One B-rep face of a CAD part: STEP entity #54834.
In plain terms, the planar face has unit normal (0, 0, 1).
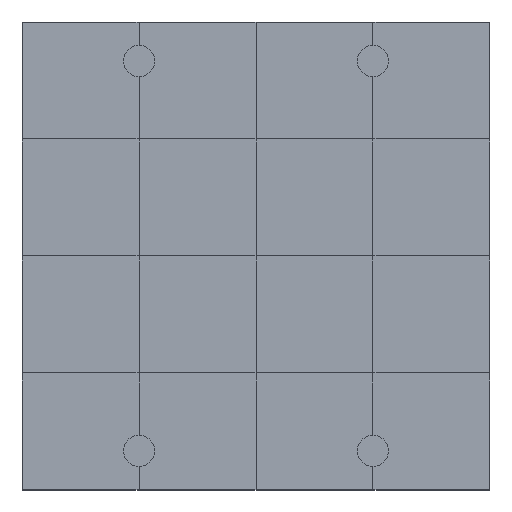
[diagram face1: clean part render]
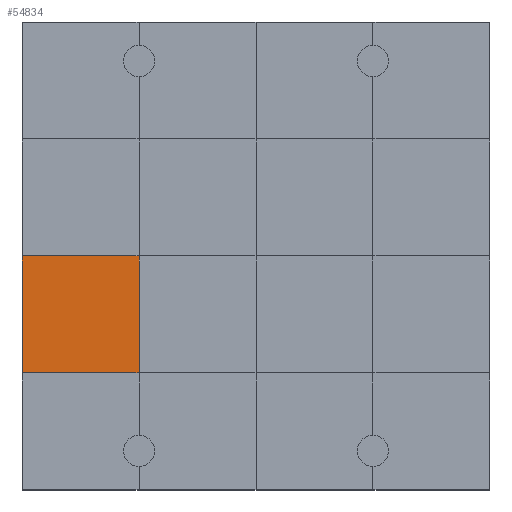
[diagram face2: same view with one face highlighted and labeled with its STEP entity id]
Its self-contained STEP definition (entity closure, numbers rounded to 3 decimals):
#54384 = VERTEX_POINT('',#54385);
#54385 = CARTESIAN_POINT('',(0.,3.,1.2));
#54399 = PLANE('',#54400);
#54400 = AXIS2_PLACEMENT_3D('',#54401,#54402,#54403);
#54401 = CARTESIAN_POINT('',(0.,3.,0.));
#54402 = DIRECTION('',(1.,0.,-0.));
#54403 = DIRECTION('',(0.,0.,1.));
#54425 = PLANE('',#54426);
#54426 = AXIS2_PLACEMENT_3D('',#54427,#54428,#54429);
#54427 = CARTESIAN_POINT('',(0.,0.,1.2));
#54428 = DIRECTION('',(0.,0.,1.));
#54429 = DIRECTION('',(1.,0.,-0.));
#54576 = VERTEX_POINT('',#54577);
#54577 = CARTESIAN_POINT('',(3.,3.,1.2));
#54598 = EDGE_CURVE('',#54384,#54576,#54599,.T.);
#54599 = SURFACE_CURVE('',#54600,(#54604,#54611),.PCURVE_S1.);
#54600 = LINE('',#54601,#54602);
#54601 = CARTESIAN_POINT('',(0.,3.,1.2));
#54602 = VECTOR('',#54603,1.);
#54603 = DIRECTION('',(1.,0.,-0.));
#54604 = PCURVE('',#54425,#54605);
#54605 = DEFINITIONAL_REPRESENTATION('',(#54606),#54610);
#54606 = LINE('',#54607,#54608);
#54607 = CARTESIAN_POINT('',(0.,3.));
#54608 = VECTOR('',#54609,1.);
#54609 = DIRECTION('',(1.,0.));
#54610 = ( GEOMETRIC_REPRESENTATION_CONTEXT(2) 
PARAMETRIC_REPRESENTATION_CONTEXT() REPRESENTATION_CONTEXT('2D SPACE',''
  ) );
#54611 = PCURVE('',#54612,#54617);
#54612 = PLANE('',#54613);
#54613 = AXIS2_PLACEMENT_3D('',#54614,#54615,#54616);
#54614 = CARTESIAN_POINT('',(0.,3.,1.2));
#54615 = DIRECTION('',(0.,0.,1.));
#54616 = DIRECTION('',(1.,0.,-0.));
#54617 = DEFINITIONAL_REPRESENTATION('',(#54618),#54622);
#54618 = LINE('',#54619,#54620);
#54619 = CARTESIAN_POINT('',(0.,0.));
#54620 = VECTOR('',#54621,1.);
#54621 = DIRECTION('',(1.,0.));
#54622 = ( GEOMETRIC_REPRESENTATION_CONTEXT(2) 
PARAMETRIC_REPRESENTATION_CONTEXT() REPRESENTATION_CONTEXT('2D SPACE',''
  ) );
#54657 = VERTEX_POINT('',#54658);
#54658 = CARTESIAN_POINT('',(0.,6.,1.2));
#54684 = EDGE_CURVE('',#54384,#54657,#54685,.T.);
#54685 = SURFACE_CURVE('',#54686,(#54690,#54697),.PCURVE_S1.);
#54686 = LINE('',#54687,#54688);
#54687 = CARTESIAN_POINT('',(0.,3.,1.2));
#54688 = VECTOR('',#54689,1.);
#54689 = DIRECTION('',(-0.,1.,0.));
#54690 = PCURVE('',#54399,#54691);
#54691 = DEFINITIONAL_REPRESENTATION('',(#54692),#54696);
#54692 = LINE('',#54693,#54694);
#54693 = CARTESIAN_POINT('',(1.2,0.));
#54694 = VECTOR('',#54695,1.);
#54695 = DIRECTION('',(0.,-1.));
#54696 = ( GEOMETRIC_REPRESENTATION_CONTEXT(2) 
PARAMETRIC_REPRESENTATION_CONTEXT() REPRESENTATION_CONTEXT('2D SPACE',''
  ) );
#54697 = PCURVE('',#54612,#54698);
#54698 = DEFINITIONAL_REPRESENTATION('',(#54699),#54703);
#54699 = LINE('',#54700,#54701);
#54700 = CARTESIAN_POINT('',(0.,0.));
#54701 = VECTOR('',#54702,1.);
#54702 = DIRECTION('',(0.,1.));
#54703 = ( GEOMETRIC_REPRESENTATION_CONTEXT(2) 
PARAMETRIC_REPRESENTATION_CONTEXT() REPRESENTATION_CONTEXT('2D SPACE',''
  ) );
#54834 = ADVANCED_FACE('',(#54835),#54612,.T.);
#54835 = FACE_BOUND('',#54836,.T.);
#54836 = EDGE_LOOP('',(#54837,#54838,#54839,#54867));
#54837 = ORIENTED_EDGE('',*,*,#54684,.F.);
#54838 = ORIENTED_EDGE('',*,*,#54598,.T.);
#54839 = ORIENTED_EDGE('',*,*,#54840,.T.);
#54840 = EDGE_CURVE('',#54576,#54841,#54843,.T.);
#54841 = VERTEX_POINT('',#54842);
#54842 = CARTESIAN_POINT('',(3.,6.,1.2));
#54843 = SURFACE_CURVE('',#54844,(#54848,#54855),.PCURVE_S1.);
#54844 = LINE('',#54845,#54846);
#54845 = CARTESIAN_POINT('',(3.,3.,1.2));
#54846 = VECTOR('',#54847,1.);
#54847 = DIRECTION('',(-0.,1.,0.));
#54848 = PCURVE('',#54612,#54849);
#54849 = DEFINITIONAL_REPRESENTATION('',(#54850),#54854);
#54850 = LINE('',#54851,#54852);
#54851 = CARTESIAN_POINT('',(3.,0.));
#54852 = VECTOR('',#54853,1.);
#54853 = DIRECTION('',(0.,1.));
#54854 = ( GEOMETRIC_REPRESENTATION_CONTEXT(2) 
PARAMETRIC_REPRESENTATION_CONTEXT() REPRESENTATION_CONTEXT('2D SPACE',''
  ) );
#54855 = PCURVE('',#54856,#54861);
#54856 = PLANE('',#54857);
#54857 = AXIS2_PLACEMENT_3D('',#54858,#54859,#54860);
#54858 = CARTESIAN_POINT('',(3.,3.,1.2));
#54859 = DIRECTION('',(0.,0.,1.));
#54860 = DIRECTION('',(1.,0.,-0.));
#54861 = DEFINITIONAL_REPRESENTATION('',(#54862),#54866);
#54862 = LINE('',#54863,#54864);
#54863 = CARTESIAN_POINT('',(0.,0.));
#54864 = VECTOR('',#54865,1.);
#54865 = DIRECTION('',(0.,1.));
#54866 = ( GEOMETRIC_REPRESENTATION_CONTEXT(2) 
PARAMETRIC_REPRESENTATION_CONTEXT() REPRESENTATION_CONTEXT('2D SPACE',''
  ) );
#54867 = ORIENTED_EDGE('',*,*,#54868,.F.);
#54868 = EDGE_CURVE('',#54657,#54841,#54869,.T.);
#54869 = SURFACE_CURVE('',#54870,(#54874,#54881),.PCURVE_S1.);
#54870 = LINE('',#54871,#54872);
#54871 = CARTESIAN_POINT('',(0.,6.,1.2));
#54872 = VECTOR('',#54873,1.);
#54873 = DIRECTION('',(1.,0.,-0.));
#54874 = PCURVE('',#54612,#54875);
#54875 = DEFINITIONAL_REPRESENTATION('',(#54876),#54880);
#54876 = LINE('',#54877,#54878);
#54877 = CARTESIAN_POINT('',(0.,3.));
#54878 = VECTOR('',#54879,1.);
#54879 = DIRECTION('',(1.,0.));
#54880 = ( GEOMETRIC_REPRESENTATION_CONTEXT(2) 
PARAMETRIC_REPRESENTATION_CONTEXT() REPRESENTATION_CONTEXT('2D SPACE',''
  ) );
#54881 = PCURVE('',#54882,#54887);
#54882 = PLANE('',#54883);
#54883 = AXIS2_PLACEMENT_3D('',#54884,#54885,#54886);
#54884 = CARTESIAN_POINT('',(0.,6.,1.2));
#54885 = DIRECTION('',(0.,0.,1.));
#54886 = DIRECTION('',(1.,0.,-0.));
#54887 = DEFINITIONAL_REPRESENTATION('',(#54888),#54892);
#54888 = LINE('',#54889,#54890);
#54889 = CARTESIAN_POINT('',(0.,0.));
#54890 = VECTOR('',#54891,1.);
#54891 = DIRECTION('',(1.,0.));
#54892 = ( GEOMETRIC_REPRESENTATION_CONTEXT(2) 
PARAMETRIC_REPRESENTATION_CONTEXT() REPRESENTATION_CONTEXT('2D SPACE',''
  ) );
